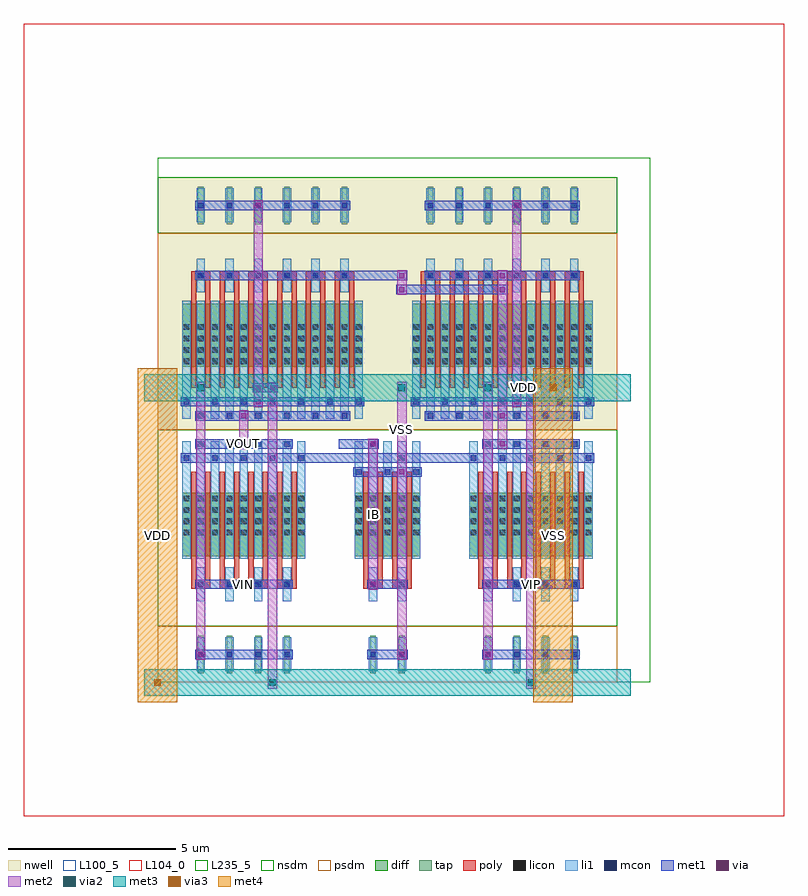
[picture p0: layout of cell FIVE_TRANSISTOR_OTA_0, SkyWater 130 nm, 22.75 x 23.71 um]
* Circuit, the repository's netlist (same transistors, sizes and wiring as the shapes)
* NGSPICE file created from FIVE_TRANSISTOR_OTA_0.ext - technology: sky130A

.subckt NMOS_4T_44724725_X4_Y1_1774868940 a_200_252# a_230_378# a_147_378# a_241_1232#
X0 a_230_378# a_200_252# a_147_378# a_241_1232# sky130_fd_pr__nfet_01v8 ad=0.2646 pd=2.17 as=0.2646 ps=2.17 w=1.89 l=0.15 M=8
.ends

.subckt SCM_NMOS_10406270_X1_Y1_1774868942 a_200_252# a_402_378# a_147_378#
X0 a_402_378# a_200_252# a_147_378# a_147_378# sky130_fd_pr__nfet_01v8 ad=0.2646 pd=2.17 as=0.2646 ps=2.17 w=1.89 l=0.15 M=2
X1 a_200_252# a_200_252# a_147_378# a_147_378# sky130_fd_pr__nfet_01v8 ad=0.2646 pd=2.17 as=0.50085 ps=4.31 w=1.89 l=0.15 M=2
.ends

.subckt PMOS_S_54676500_X6_Y1_1774868941 a_200_252# a_230_378# w_0_0#
X0 a_230_378# a_200_252# w_0_0# w_0_0# sky130_fd_pr__pfet_01v8 ad=0.2646 pd=2.17 as=0.2646 ps=2.17 w=1.89 l=0.15 M=12
.ends

.subckt DCL_PMOS_S_11026668_X6_Y1_1774868939 a_200_252# w_0_0#
X0 a_200_252# a_200_252# w_0_0# w_0_0# sky130_fd_pr__pfet_01v8 ad=0.2646 pd=2.17 as=0.2646 ps=2.17 w=1.89 l=0.15 M=12
.ends

.subckt FIVE_TRANSISTOR_OTA_0 IB VOUT VIP VIN VSS VDD
XNMOS_4T_44724725_X4_Y1_1774868940_0 VIN VOUT m1_860_1316# VSS NMOS_4T_44724725_X4_Y1_1774868940
XNMOS_4T_44724725_X4_Y1_1774868940_1 VIP m1_2032_1400# m1_860_1316# VSS NMOS_4T_44724725_X4_Y1_1774868940
XSCM_NMOS_10406270_X1_Y1_1774868942_0 IB m1_860_1316# VSS SCM_NMOS_10406270_X1_Y1_1774868942
XPMOS_S_54676500_X6_Y1_1774868941_0 m1_2032_1400# VOUT VDD PMOS_S_54676500_X6_Y1_1774868941
XDCL_PMOS_S_11026668_X6_Y1_1774868939_0 m1_2032_1400# VDD DCL_PMOS_S_11026668_X6_Y1_1774868939
.ends

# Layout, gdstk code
from math import pi, radians
import gdstk
lib = gdstk.Library(unit=1e-6, precision=1e-09)
def R(c, l, rs):  # rectangles x0, y0, x1, y1
    for r in rs: c.add(gdstk.rectangle(r[:2], r[2:], *l))
def A(c, l, x, y, w, h, nx, ny, dx, dy):  # array of equal rectangles
    R(c, l, [(x+i*dx, y+j*dy, x+i*dx+w, y+j*dy+h) for i in range(nx) for j in range(ny)])
def P(c, l, *ps):  # polygons
    for p in ps: c.add(gdstk.Polygon(p, *l))
nwell = (64, 20)
diff = (65, 20)
tap = (65, 44)
poly = (66, 20)
licon = (66, 44)
li1 = (67, 20)
mcon = (67, 44)
met1 = (68, 20)
via = (68, 44)
met2 = (69, 20)
via2 = (69, 44)
met3 = (70, 20)
via3 = (70, 44)
met4 = (71, 20)
nsdm = (93, 44)
psdm = (94, 20)
L100_5 = (100, 5)
L104_0 = (104, 0)
L235_5 = (235, 5)

scm_nmos_10406270_x1_y1_ = lib.new_cell('SCM_NMOS_10406270_X1_Y1_1774868942')
R(scm_nmos_10406270_x1_y1_, diff, [(0.735,1.89,2.705,3.78)])
R(scm_nmos_10406270_x1_y1_, tap, [(1.205,6.16,1.375,7.28), (2.065,6.16,2.235,7.28)])
A(scm_nmos_10406270_x1_y1_, poly, 1, 1.26, 0.15, 3.36, 4, 1, 0.43, 0)
R(scm_nmos_10406270_x1_y1_, poly, [(1,4.485,1.58,4.755), (1.86,4.485,2.44,4.755)])
A(scm_nmos_10406270_x1_y1_, licon, 0.775, 1.97, 0.17, 0.17, 3, 4, 0.43, 0.34)
A(scm_nmos_10406270_x1_y1_, licon, 1.635, 1.97, 0.17, 0.17, 3, 4, 0.43, 0.34)
R(scm_nmos_10406270_x1_y1_, licon, [(1.205,4.535,1.375,4.705), (2.065,4.535,2.235,4.705), (1.205,6.635,1.375,6.805), (2.065,6.635,2.235,6.805)])
A(scm_nmos_10406270_x1_y1_, li1, 0.735, 0.335, 0.25, 3.53, 5, 1, 0.43, 0)
R(scm_nmos_10406270_x1_y1_, li1, [(1.165,4.115,1.415,5.125), (2.025,4.115,2.275,5.125), (1.165,6.215,1.415,7.225), (2.025,6.215,2.275,7.225)])
A(scm_nmos_10406270_x1_y1_, mcon, 0.775, 1.175, 0.17, 0.17, 3, 1, 0.86, 0)
R(scm_nmos_10406270_x1_y1_, mcon, [(1.205,0.335,1.375,0.505), (2.065,0.755,2.235,0.925), (1.205,4.535,1.375,4.705), (2.065,4.535,2.235,4.705), (1.205,6.635,1.375,6.805), (2.065,6.635,2.235,6.805)])
R(scm_nmos_10406270_x1_y1_, met1, [(0.26,0.28,1.46,0.56), (1.12,0.7,2.32,0.98), (0.69,1.12,2.75,1.4), (1.12,4.48,2.32,4.76), (1.12,6.58,2.32,6.86)])
R(scm_nmos_10406270_x1_y1_, via, [(1.215,0.345,1.365,0.495), (2.075,1.185,2.225,1.335), (1.215,4.545,1.365,4.695), (2.075,6.645,2.225,6.795)])
R(scm_nmos_10406270_x1_y1_, met2, [(1.15,0.26,1.43,4.78), (2.01,1.1,2.29,6.88)])
R(scm_nmos_10406270_x1_y1_, nsdm, [(0,0,3.44,5.88)])
R(scm_nmos_10406270_x1_y1_, psdm, [(0,5.88,3.44,7.56)])
R(scm_nmos_10406270_x1_y1_, L100_5, [(0,0,3.44,7.56)])

dcl_pmos_s_11026668_x6_y = lib.new_cell('DCL_PMOS_S_11026668_X6_Y1_1774868939')
R(dcl_pmos_s_11026668_x6_y, nwell, [(0,0,6.88,7.56)])
R(dcl_pmos_s_11026668_x6_y, diff, [(0.735,1.89,6.145,3.78)])
A(dcl_pmos_s_11026668_x6_y, tap, 1.205, 6.16, 0.17, 1.12, 6, 1, 0.86, 0)
A(dcl_pmos_s_11026668_x6_y, poly, 1, 1.26, 0.15, 3.36, 12, 1, 0.43, 0)
A(dcl_pmos_s_11026668_x6_y, poly, 1, 4.485, 0.58, 0.27, 6, 1, 0.86, 0)
A(dcl_pmos_s_11026668_x6_y, licon, 0.775, 1.97, 0.17, 0.17, 3, 4, 0.43, 0.34)
A(dcl_pmos_s_11026668_x6_y, licon, 1.635, 1.97, 0.17, 0.17, 3, 4, 0.43, 0.34)
A(dcl_pmos_s_11026668_x6_y, licon, 2.495, 1.97, 0.17, 0.17, 3, 4, 0.43, 0.34)
A(dcl_pmos_s_11026668_x6_y, licon, 3.355, 1.97, 0.17, 0.17, 3, 4, 0.43, 0.34)
A(dcl_pmos_s_11026668_x6_y, licon, 4.215, 1.97, 0.17, 0.17, 3, 4, 0.43, 0.34)
A(dcl_pmos_s_11026668_x6_y, licon, 5.075, 1.97, 0.17, 0.17, 3, 4, 0.43, 0.34)
A(dcl_pmos_s_11026668_x6_y, licon, 1.205, 4.535, 0.17, 0.17, 6, 2, 0.86, 2.1)
A(dcl_pmos_s_11026668_x6_y, li1, 0.735, 0.335, 0.25, 3.53, 13, 1, 0.43, 0)
A(dcl_pmos_s_11026668_x6_y, li1, 1.165, 4.115, 0.25, 1.01, 6, 2, 0.86, 2.1)
A(dcl_pmos_s_11026668_x6_y, mcon, 1.205, 0.335, 0.17, 0.17, 6, 2, 0.86, 4.2)
A(dcl_pmos_s_11026668_x6_y, mcon, 0.775, 0.755, 0.17, 0.17, 7, 1, 0.86, 0)
A(dcl_pmos_s_11026668_x6_y, mcon, 1.205, 6.635, 0.17, 0.17, 6, 1, 0.86, 0)
R(dcl_pmos_s_11026668_x6_y, met1, [(1.12,0.28,5.76,0.56), (0.69,0.7,6.19,0.98), (1.12,4.48,5.76,4.76), (1.12,6.58,5.76,6.86)])
R(dcl_pmos_s_11026668_x6_y, via, [(3.365,0.345,3.515,0.495), (3.795,0.765,3.945,0.915), (3.365,4.545,3.515,4.695), (3.795,6.645,3.945,6.795)])
R(dcl_pmos_s_11026668_x6_y, met2, [(3.3,0.26,3.58,4.78), (3.73,0.68,4.01,6.88)])
R(dcl_pmos_s_11026668_x6_y, nsdm, [(0,5.88,6.88,7.56)])
R(dcl_pmos_s_11026668_x6_y, psdm, [(0,0,6.88,5.88)])
R(dcl_pmos_s_11026668_x6_y, L100_5, [(0,0,6.88,7.56)])

pmos_s_54676500_x6_y1_17 = lib.new_cell('PMOS_S_54676500_X6_Y1_1774868941')
R(pmos_s_54676500_x6_y1_17, nwell, [(0,0,6.88,7.56)])
R(pmos_s_54676500_x6_y1_17, diff, [(0.735,1.89,6.145,3.78)])
A(pmos_s_54676500_x6_y1_17, tap, 1.205, 6.16, 0.17, 1.12, 6, 1, 0.86, 0)
A(pmos_s_54676500_x6_y1_17, poly, 1, 1.26, 0.15, 3.36, 12, 1, 0.43, 0)
A(pmos_s_54676500_x6_y1_17, poly, 1, 4.485, 0.58, 0.27, 6, 1, 0.86, 0)
A(pmos_s_54676500_x6_y1_17, licon, 0.775, 1.97, 0.17, 0.17, 3, 4, 0.43, 0.34)
A(pmos_s_54676500_x6_y1_17, licon, 1.635, 1.97, 0.17, 0.17, 3, 4, 0.43, 0.34)
A(pmos_s_54676500_x6_y1_17, licon, 2.495, 1.97, 0.17, 0.17, 3, 4, 0.43, 0.34)
A(pmos_s_54676500_x6_y1_17, licon, 3.355, 1.97, 0.17, 0.17, 3, 4, 0.43, 0.34)
A(pmos_s_54676500_x6_y1_17, licon, 4.215, 1.97, 0.17, 0.17, 3, 4, 0.43, 0.34)
A(pmos_s_54676500_x6_y1_17, licon, 5.075, 1.97, 0.17, 0.17, 3, 4, 0.43, 0.34)
A(pmos_s_54676500_x6_y1_17, licon, 1.205, 4.535, 0.17, 0.17, 6, 2, 0.86, 2.1)
A(pmos_s_54676500_x6_y1_17, li1, 0.735, 0.335, 0.25, 3.53, 13, 1, 0.43, 0)
A(pmos_s_54676500_x6_y1_17, li1, 1.165, 4.115, 0.25, 1.01, 6, 2, 0.86, 2.1)
A(pmos_s_54676500_x6_y1_17, mcon, 1.205, 0.335, 0.17, 0.17, 6, 2, 0.86, 4.2)
A(pmos_s_54676500_x6_y1_17, mcon, 0.775, 0.755, 0.17, 0.17, 7, 1, 0.86, 0)
A(pmos_s_54676500_x6_y1_17, mcon, 1.205, 6.635, 0.17, 0.17, 6, 1, 0.86, 0)
R(pmos_s_54676500_x6_y1_17, met1, [(1.12,0.28,5.76,0.56), (0.69,0.7,6.19,0.98), (1.12,4.48,5.76,4.76), (1.12,6.58,5.76,6.86)])
R(pmos_s_54676500_x6_y1_17, via, [(3.795,0.765,3.945,0.915), (3.795,6.645,3.945,6.795)])
R(pmos_s_54676500_x6_y1_17, met2, [(3.73,0.68,4.01,6.88)])
R(pmos_s_54676500_x6_y1_17, nsdm, [(0,5.88,6.88,7.56)])
R(pmos_s_54676500_x6_y1_17, psdm, [(0,0,6.88,5.88)])
R(pmos_s_54676500_x6_y1_17, L100_5, [(0,0,6.88,7.56)])

nmos_4t_44724725_x4_y1_1 = lib.new_cell('NMOS_4T_44724725_X4_Y1_1774868940')
R(nmos_4t_44724725_x4_y1_1, diff, [(0.735,1.89,4.425,3.78)])
A(nmos_4t_44724725_x4_y1_1, tap, 1.205, 6.16, 0.17, 1.12, 4, 1, 0.86, 0)
A(nmos_4t_44724725_x4_y1_1, poly, 1, 1.26, 0.15, 3.36, 8, 1, 0.43, 0)
A(nmos_4t_44724725_x4_y1_1, poly, 1, 4.485, 0.58, 0.27, 4, 1, 0.86, 0)
A(nmos_4t_44724725_x4_y1_1, licon, 0.775, 1.97, 0.17, 0.17, 3, 4, 0.43, 0.34)
A(nmos_4t_44724725_x4_y1_1, licon, 1.635, 1.97, 0.17, 0.17, 3, 4, 0.43, 0.34)
A(nmos_4t_44724725_x4_y1_1, licon, 2.495, 1.97, 0.17, 0.17, 3, 4, 0.43, 0.34)
A(nmos_4t_44724725_x4_y1_1, licon, 3.355, 1.97, 0.17, 0.17, 3, 4, 0.43, 0.34)
A(nmos_4t_44724725_x4_y1_1, licon, 1.205, 4.535, 0.17, 0.17, 4, 2, 0.86, 2.1)
A(nmos_4t_44724725_x4_y1_1, li1, 0.735, 0.335, 0.25, 3.53, 9, 1, 0.43, 0)
A(nmos_4t_44724725_x4_y1_1, li1, 1.165, 4.115, 0.25, 1.01, 4, 2, 0.86, 2.1)
A(nmos_4t_44724725_x4_y1_1, mcon, 1.205, 0.335, 0.17, 0.17, 4, 2, 0.86, 4.2)
A(nmos_4t_44724725_x4_y1_1, mcon, 0.775, 0.755, 0.17, 0.17, 5, 1, 0.86, 0)
A(nmos_4t_44724725_x4_y1_1, mcon, 1.205, 6.635, 0.17, 0.17, 4, 1, 0.86, 0)
R(nmos_4t_44724725_x4_y1_1, met1, [(1.12,0.28,4.04,0.56), (0.69,0.7,4.47,0.98), (1.12,4.48,4.04,4.76), (1.12,6.58,4.04,6.86)])
R(nmos_4t_44724725_x4_y1_1, nsdm, [(0,0,5.16,5.88)])
R(nmos_4t_44724725_x4_y1_1, psdm, [(0,5.88,5.16,7.56)])
R(nmos_4t_44724725_x4_y1_1, L100_5, [(0,0,5.16,7.56)])

five_transistor_ota_0 = lib.new_cell('FIVE_TRANSISTOR_OTA_0')
R(five_transistor_ota_0, met1, [(1.13,0.7,1.45,0.98), (1.13,0.7,1.45,0.98), (9.73,0.7,10.05,0.98), (9.73,0.7,10.05,0.98), (9.73,0.7,10.05,0.98), (4.3,6.58,6.45,6.86), (7.31,6.58,9.46,6.86), (2.42,7,2.74,7.28), (2.42,7,2.74,7.28), (10.16,7,10.48,7.28), (10.16,7,10.48,7.28), (2.42,7.84,2.74,8.12), (2.42,7.84,2.74,8.12), (2.85,8.68,3.17,8.96), (2.85,8.68,3.17,8.96), (3.01,8.68,3.44,8.96), (3.28,8.68,3.6,8.96), (3.28,8.68,3.6,8.96), (10.59,8.68,10.91,8.96), (10.59,8.68,10.91,8.96), (10.59,8.68,10.91,8.96), (10.75,8.68,11.18,8.96), (11.02,8.68,11.34,8.96), (11.02,8.68,11.34,8.96), (11.02,8.68,11.34,8.96), (7.15,11.62,7.47,11.9), (7.15,11.62,7.47,11.9), (7.15,11.62,7.47,11.9), (7.15,11.62,7.47,11.9), (7.31,11.62,10.32,11.9), (10.16,11.62,10.48,11.9), (10.16,11.62,10.48,11.9), (10.16,11.62,10.48,11.9), (10.16,11.62,10.48,11.9), (5.59,12.04,7.31,12.32), (7.15,12.04,7.47,12.32), (7.15,12.04,7.47,12.32), (7.15,12.04,7.47,12.32), (7.15,12.04,7.47,12.32)])
P(five_transistor_ota_0, met1, [(0,0),(0,0),(0,0),(0,0)],
  [(0,0),(0,0),(0,0),(0,0)],
  [(0,0),(0,0),(0,0),(0,0)],
  [(0,0),(0,0),(0,0),(0,0)],
  [(0,0),(0,0),(0,0),(0,0)],
  [(0,0),(0,0),(0,0),(0,0)],
  [(0,0),(0,0),(0,0),(0,0)],
  [(0,0),(0,0),(0,0),(0,0)],
  [(0,0),(0,0),(0,0),(0,0)],
  [(0,0),(0,0),(0,0),(0,0)],
  [(0,0),(0,0),(0,0),(0,0)],
  [(0,0),(0,0),(0,0),(0,0)],
  [(0,0),(0,0),(0,0),(0,0)],
  [(0,0),(0,0),(0,0),(0,0)])
R(five_transistor_ota_0, via, [(1.215,0.765,1.365,0.915), (1.215,0.765,1.365,0.915), (9.815,0.765,9.965,0.915), (9.815,0.765,9.965,0.915), (9.815,0.765,9.965,0.915), (2.505,7.065,2.655,7.215), (2.505,7.065,2.655,7.215), (10.245,7.065,10.395,7.215), (10.245,7.065,10.395,7.215), (2.505,7.905,2.655,8.055), (2.505,7.905,2.655,8.055), (2.935,8.745,3.085,8.895), (2.935,8.745,3.085,8.895), (3.365,8.745,3.515,8.895), (3.365,8.745,3.515,8.895), (10.675,8.745,10.825,8.895), (10.675,8.745,10.825,8.895), (10.675,8.745,10.825,8.895), (11.105,8.745,11.255,8.895), (11.105,8.745,11.255,8.895), (11.105,8.745,11.255,8.895), (7.235,11.685,7.385,11.835), (7.235,11.685,7.385,11.835), (7.235,11.685,7.385,11.835), (7.235,11.685,7.385,11.835), (10.245,11.685,10.395,11.835), (10.245,11.685,10.395,11.835), (10.245,11.685,10.395,11.835), (10.245,11.685,10.395,11.835), (7.235,12.105,7.385,12.255), (7.235,12.105,7.385,12.255), (7.235,12.105,7.385,12.255), (7.235,12.105,7.385,12.255)])
R(five_transistor_ota_0, met2, [(3.3,-0.185,3.58,0.185), (3.3,-0.185,3.58,0.185), (11.04,-0.185,11.32,0.185), (11.04,-0.185,11.32,0.185), (11.04,-0.185,11.32,0.185), (3.3,0,3.58,8.82), (11.04,0,11.32,8.82), (1.15,0.68,1.43,1), (1.15,0.68,1.43,1), (9.75,0.68,10.03,1), (9.75,0.68,10.03,1), (9.75,0.68,10.03,1), (1.15,0.84,1.43,8.82), (9.75,0.84,10.03,8.82), (7.17,6.3,7.45,8.82), (2.44,6.98,2.72,7.3), (2.44,6.98,2.72,7.3), (10.18,6.98,10.46,7.3), (10.18,6.98,10.46,7.3), (2.44,7.14,2.72,7.98), (10.18,7.14,10.46,7.98), (2.44,7.82,2.72,8.14), (2.44,7.82,2.72,8.14), (1.15,8.635,1.43,9.005), (1.15,8.635,1.43,9.005), (7.17,8.635,7.45,9.005), (7.17,8.635,7.45,9.005), (7.17,8.635,7.45,9.005), (7.17,8.635,7.45,9.005), (9.75,8.635,10.03,9.005), (9.75,8.635,10.03,9.005), (9.75,8.635,10.03,9.005), (2.87,8.66,3.15,8.98), (2.87,8.66,3.15,8.98), (3.3,8.66,3.58,8.98), (3.3,8.66,3.58,8.98), (10.61,8.66,10.89,8.98), (10.61,8.66,10.89,8.98), (10.61,8.66,10.89,8.98), (11.04,8.66,11.32,8.98), (11.04,8.66,11.32,8.98), (11.04,8.66,11.32,8.98), (7.17,11.6,7.45,11.92), (7.17,11.6,7.45,11.92), (7.17,11.6,7.45,11.92), (7.17,11.6,7.45,11.92), (10.18,11.6,10.46,11.92), (10.18,11.6,10.46,11.92), (10.18,11.6,10.46,11.92), (10.18,11.6,10.46,11.92), (7.17,11.76,7.45,12.18), (7.17,12.02,7.45,12.34), (7.17,12.02,7.45,12.34), (7.17,12.02,7.45,12.34), (7.17,12.02,7.45,12.34)])
P(five_transistor_ota_0, met2, [(0,0),(0,0),(0,0),(0,0)],
  [(0,0),(0,0),(0,0),(0,0)],
  [(0,0),(0,0),(0,0),(0,0)],
  [(0,0),(0,0),(0,0),(0,0)],
  [(0,0),(0,0),(0,0),(0,0)],
  [(0,0),(0,0),(0,0),(0,0)])
R(five_transistor_ota_0, via2, [(3.34,-0.1,3.54,0.1), (3.34,-0.1,3.54,0.1), (11.08,-0.1,11.28,0.1), (11.08,-0.1,11.28,0.1), (11.08,-0.1,11.28,0.1), (1.19,8.72,1.39,8.92), (1.19,8.72,1.39,8.92), (7.21,8.72,7.41,8.92), (7.21,8.72,7.41,8.92), (7.21,8.72,7.41,8.92), (7.21,8.72,7.41,8.92), (9.79,8.72,9.99,8.92), (9.79,8.72,9.99,8.92), (9.79,8.72,9.99,8.92)])
A(five_transistor_ota_0, met3, -0.4, -0.4, 4.24, 0.8, 3, 2, 3.44, 8.82)
R(five_transistor_ota_0, met3, [(-0.165,-0.4,0.165,0.4), (3.275,-0.4,3.605,0.4), (3.275,-0.4,3.605,0.4), (9.92,-0.4,12.24,0.4), (11.015,-0.4,11.345,0.4), (11.015,-0.4,11.345,0.4), (11.015,-0.4,11.345,0.4), (11.44,-0.4,14.16,0.4), (1.125,8.42,1.455,9.22), (1.125,8.42,1.455,9.22), (7.145,8.42,7.475,9.22), (7.145,8.42,7.475,9.22), (7.145,8.42,7.475,9.22), (7.145,8.42,7.475,9.22), (9.725,8.42,10.055,9.22), (9.725,8.42,10.055,9.22), (9.725,8.42,10.055,9.22), (9.92,8.42,12.24,9.22), (11.44,8.42,14.16,9.22), (11.675,8.42,12.005,9.22)])
R(five_transistor_ota_0, via3, [(-0.1,-0.1,0.1,0.1), (11.74,8.72,11.94,8.92)])
R(five_transistor_ota_0, met4, [(-0.59,-0.59,0.59,9.41), (11.25,-0.59,12.43,9.41), (-0.59,-0.165,0.59,0.165), (11.25,8.655,12.43,8.985)])
R(five_transistor_ota_0, L104_0, [(-4,-4,18.75,19.71)])
R(five_transistor_ota_0, L235_5, [(0,0,14.75,15.71)])
five_transistor_ota_0.add(gdstk.Reference(scm_nmos_10406270_x1_y1_, (5.16,7.56), x_reflection=True))
five_transistor_ota_0.add(gdstk.Reference(dcl_pmos_s_11026668_x6_y, (6.88,7.56)))
five_transistor_ota_0.add(gdstk.Reference(pmos_s_54676500_x6_y1_17, (6.88,7.56), rotation=pi, x_reflection=True))
five_transistor_ota_0.add(gdstk.Reference(nmos_4t_44724725_x4_y1_1, (8.6,7.56), x_reflection=True))
five_transistor_ota_0.add(gdstk.Reference(nmos_4t_44724725_x4_y1_1, (5.16,7.56), rotation=pi))
five_transistor_ota_0.add(gdstk.Label('IB', (6.45,5.04), layer=69, texttype=5))
five_transistor_ota_0.add(gdstk.Label('VOUT', (2.58,7.14), layer=68, texttype=5))
five_transistor_ota_0.add(gdstk.Label('VIP', (11.18,2.94), layer=68, texttype=5))
five_transistor_ota_0.add(gdstk.Label('VIN', (2.58,2.94), layer=68, texttype=5))
five_transistor_ota_0.add(gdstk.Label('VSS', (7.31,7.56), layer=69, texttype=5))
five_transistor_ota_0.add(gdstk.Label('VSS', (11.84,4.41), layer=71, texttype=5))
five_transistor_ota_0.add(gdstk.Label('VSS', (11.84,4.41), layer=71, texttype=5))
five_transistor_ota_0.add(gdstk.Label('VSS', (11.84,4.41), layer=71, texttype=5))
five_transistor_ota_0.add(gdstk.Label('VSS', (11.84,4.41), layer=71, texttype=5))
five_transistor_ota_0.add(gdstk.Label('VSS', (11.84,4.41), layer=71, texttype=5))
five_transistor_ota_0.add(gdstk.Label('VSS', (11.84,4.41), layer=71, texttype=5))
five_transistor_ota_0.add(gdstk.Label('VSS', (11.84,4.41), layer=71, texttype=5))
five_transistor_ota_0.add(gdstk.Label('VSS', (11.84,4.41), layer=71, texttype=5))
five_transistor_ota_0.add(gdstk.Label('VDD', (0,4.41), layer=71, texttype=5))
five_transistor_ota_0.add(gdstk.Label('VDD', (10.965,8.82), layer=68, texttype=5))
five_transistor_ota_0.add(gdstk.Label('VDD', (0,4.41), layer=71, texttype=5))
five_transistor_ota_0.add(gdstk.Label('VDD', (0,4.41), layer=71, texttype=5))
five_transistor_ota_0.add(gdstk.Label('VDD', (0,4.41), layer=71, texttype=5))
five_transistor_ota_0.add(gdstk.Label('VDD', (0,4.41), layer=71, texttype=5))
five_transistor_ota_0.add(gdstk.Label('VDD', (0,4.41), layer=71, texttype=5))
five_transistor_ota_0.add(gdstk.Label('VDD', (0,4.41), layer=71, texttype=5))
five_transistor_ota_0.add(gdstk.Label('VDD', (0,4.41), layer=71, texttype=5))

lib.write_gds('FIVE_TRANSISTOR_OTA_0.gds')
